VERSION 5.8 ;
BUSBITCHARS "[]" ;
DIVIDERCHAR "/" ;
UNITS
  DATABASE MICRONS 1000 ;
END UNITS
MANUFACTURINGGRID 0.005 ;

# Synthetic two-mask stack for the mask-colour tests: M1 and M2 are double-patterned (MASK 2),
# M3 is single-patterned. Values are round numbers, not any technology's. As masks.lef, plus a
# joint corner spacing rule on M1 (the LEF/DEF reference figure's values) and one without
# SAMEMASK on M2.

PROPERTYDEFINITIONS
  LAYER LEF58_JOINTCORNERSPACING STRING ;
END PROPERTYDEFINITIONS

SITE core
  CLASS CORE ;
  SIZE 0.1 BY 1.0 ;
END core

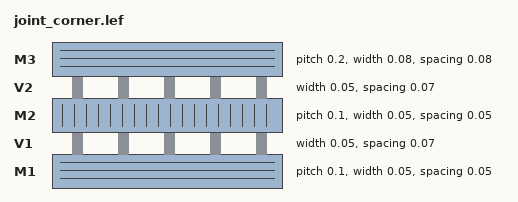
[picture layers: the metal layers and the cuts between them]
LAYER M1
  TYPE ROUTING ;
  DIRECTION HORIZONTAL ;
  PITCH 0.1 ;
  OFFSET 0.05 ;
  WIDTH 0.05 ;
  SPACING 0.05 ;
  MASK 2 ;
  PROPERTY LEF58_JOINTCORNERSPACING "JOINTCORNERSPACING 0.05 SAMEMASK JOINTWIDTH 0.07 JOINTLENGTH 0.06 EDGELENGTH 0.1 ;" ;
END M1

LAYER V1
  TYPE CUT ;
  WIDTH 0.05 ;
  SPACING 0.07 ;
END V1

LAYER M2
  TYPE ROUTING ;
  DIRECTION VERTICAL ;
  PITCH 0.1 ;
  OFFSET 0.05 ;
  WIDTH 0.05 ;
  SPACING 0.05 ;
  MASK 2 ;
  PROPERTY LEF58_JOINTCORNERSPACING "JOINTCORNERSPACING 0.05 JOINTWIDTH 0.07 JOINTLENGTH 0.06 ;" ;
END M2

LAYER V2
  TYPE CUT ;
  WIDTH 0.05 ;
  SPACING 0.07 ;
END V2

LAYER M3
  TYPE ROUTING ;
  DIRECTION HORIZONTAL ;
  PITCH 0.2 ;
  OFFSET 0.1 ;
  WIDTH 0.08 ;
  SPACING 0.08 ;
END M3

VIA V12 DEFAULT
  LAYER M1 ;
    RECT -0.05 -0.025 0.05 0.025 ;
  LAYER V1 ;
    RECT -0.025 -0.025 0.025 0.025 ;
  LAYER M2 ;
    RECT -0.025 -0.05 0.025 0.05 ;
END V12

VIA V23 DEFAULT
  LAYER M2 ;
    RECT -0.025 -0.05 0.025 0.05 ;
  LAYER V2 ;
    RECT -0.025 -0.025 0.025 0.025 ;
  LAYER M3 ;
    RECT -0.05 -0.04 0.05 0.04 ;
END V23

END LIBRARY
